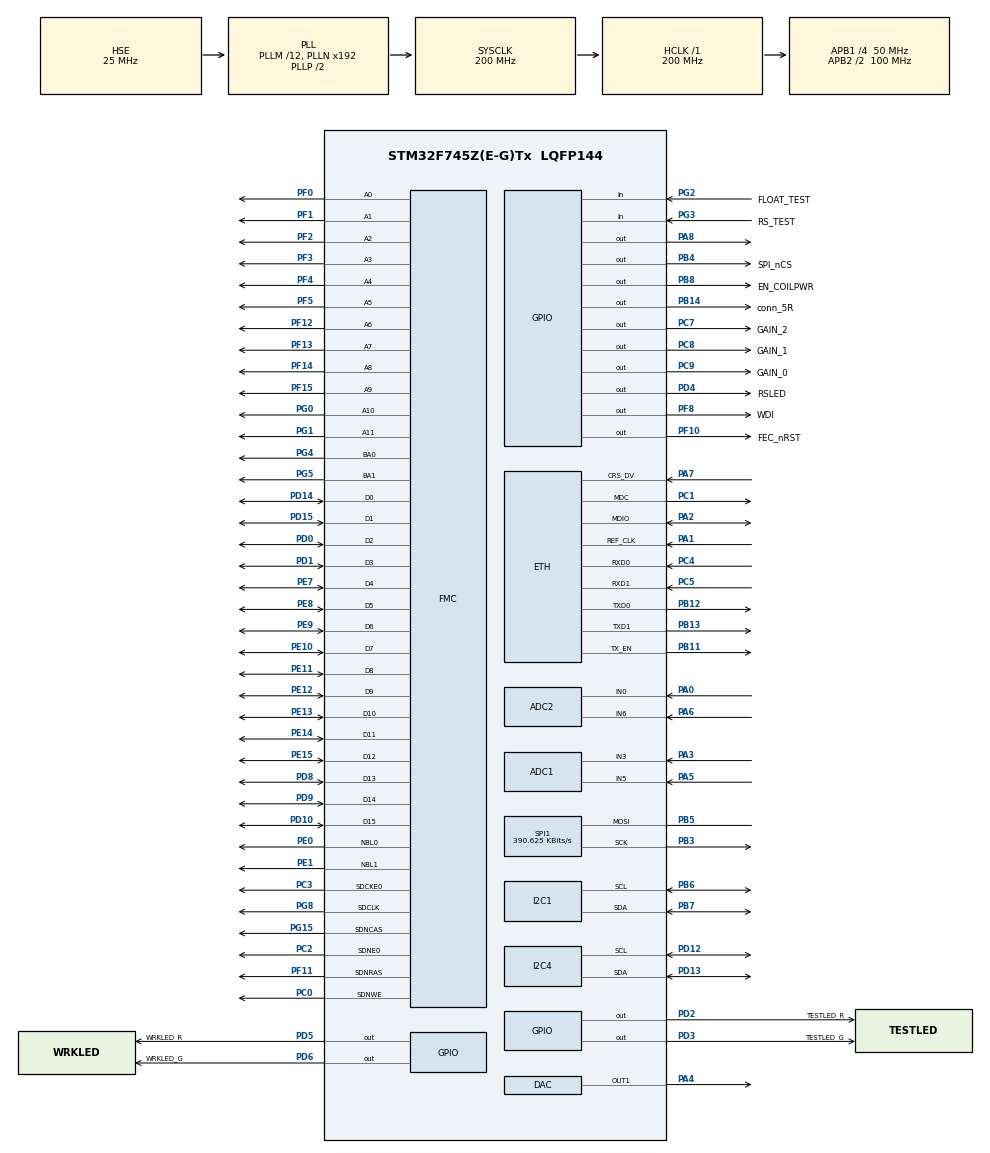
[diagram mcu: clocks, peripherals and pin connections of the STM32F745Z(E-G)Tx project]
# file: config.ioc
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ADC1.Channel-0\#ChannelRegularConversion=ADC_CHANNEL_3
ADC1.Channel-1\#ChannelRegularConversion=ADC_CHANNEL_3
ADC1.Channel-2\#ChannelRegularConversion=ADC_CHANNEL_3
ADC1.Channel-3\#ChannelRegularConversion=ADC_CHANNEL_3
ADC1.ClockPrescaler=ADC_CLOCK_SYNC_PCLK_DIV8
ADC1.ContinuousConvMode=ENABLE
ADC1.DMAContinuousRequests=ENABLE
ADC1.Mode=ADC_DUALMODE_REGSIMULT
ADC1.NbrOfConversion=4
ADC1.NbrOfConversionFlag=1
ADC1.Rank-0\#ChannelRegularConversion=1
ADC1.Rank-1\#ChannelRegularConversion=2
ADC1.Rank-2\#ChannelRegularConversion=3
ADC1.Rank-3\#ChannelRegularConversion=4
ADC1.SamplingTime-0\#ChannelRegularConversion=ADC_SAMPLETIME_3CYCLES
ADC1.SamplingTime-1\#ChannelRegularConversion=ADC_SAMPLETIME_3CYCLES
ADC1.SamplingTime-2\#ChannelRegularConversion=ADC_SAMPLETIME_3CYCLES
ADC1.SamplingTime-3\#ChannelRegularConversion=ADC_SAMPLETIME_3CYCLES
ADC1.master=1
ADC2.Channel-0\#ChannelRegularConversion=ADC_CHANNEL_0
ADC2.Channel-1\#ChannelRegularConversion=ADC_CHANNEL_0
ADC2.Channel-2\#ChannelRegularConversion=ADC_CHANNEL_0
ADC2.Channel-3\#ChannelRegularConversion=ADC_CHANNEL_0
ADC2.ClockPrescaler=ADC_CLOCK_SYNC_PCLK_DIV8
ADC2.ContinuousConvMode=ENABLE
ADC2.DMAAccessMode=ADC_DMAACCESSMODE_2
ADC2.Mode=ADC_DUALMODE_REGSIMULT
ADC2.NbrOfConversion=4
ADC2.NbrOfConversionFlag=1
ADC2.Rank-0\#ChannelRegularConversion=1
ADC2.Rank-1\#ChannelRegularConversion=2
ADC2.Rank-2\#ChannelRegularConversion=3
ADC2.Rank-3\#ChannelRegularConversion=4
ADC2.SamplingTime-0\#ChannelRegularConversion=ADC_SAMPLETIME_3CYCLES
ADC2.SamplingTime-1\#ChannelRegularConversion=ADC_SAMPLETIME_3CYCLES
ADC2.SamplingTime-2\#ChannelRegularConversion=ADC_SAMPLETIME_3CYCLES
ADC2.SamplingTime-3\#ChannelRegularConversion=ADC_SAMPLETIME_3CYCLES
CORTEX_M7.CPU_DCache=Enabled
CORTEX_M7.CPU_ICache=Enabled
CORTEX_M7.PREFETCH_ENABLE=1
DAC.DAC_Trigger=DAC_TRIGGER_SOFTWARE
Dma.ADC1.0.Direction=DMA_PERIPH_TO_MEMORY
Dma.ADC1.0.FIFOMode=DMA_FIFOMODE_DISABLE
Dma.ADC1.0.Instance=DMA2_Stream0
Dma.ADC1.0.MemDataAlignment=DMA_MDATAALIGN_WORD
Dma.ADC1.0.MemInc=DMA_MINC_ENABLE
Dma.ADC1.0.Mode=DMA_CIRCULAR
Dma.ADC1.0.PeriphDataAlignment=DMA_PDATAALIGN_WORD
Dma.ADC1.0.PeriphInc=DMA_PINC_DISABLE
Dma.ADC1.0.Priority=DMA_PRIORITY_HIGH
Dma.Request0=ADC1
ETH.MediaInterface=ETH_MEDIA_INTERFACE_RMII
ETH.PhyAddress=0
FMC.CASLatency1=FMC_SDRAM_CAS_LATENCY_2
FMC.ReadBurst1=FMC_SDRAM_RBURST_ENABLE
FMC.WriteProtection1=FMC_SDRAM_WRITE_PROTECTION_DISABLE
FREERTOS.Mutexes01=myMutex01,Dynamic,NULL
FREERTOS.Tasks01=defaultTask,0,128,StartDefaultTask,Default,NULL,Dynamic,NULL,NULL
FREERTOS.configENABLE_FPU=1
I2C1.Analog_Filter=I2C_ANALOGFILTER_DISABLE
I2C1.Timing=0x00C0EFFF
I2C4.Analog_Filter=I2C_ANALOGFILTER_DISABLE
I2C4.Timing=0x00C0EFFF
LWIP.GATEWAY_ADDRESS=192.168.000.001
LWIP.IP_ADDRESS=192.168.000.010
LWIP.LWIP_DHCP=0
LWIP.LWIP_HTTPD=0
LWIP.NETMASK_ADDRESS=255.255.255.000
LWIP.Version=v2.1.2_Cube
Mcu.Family=STM32F7
Mcu.Name=STM32F745Z(E-G)Tx
Mcu.Package=LQFP144
NVIC.DMA2_Stream0_IRQn=true\:0\:0\:false\:false\:true\:true\:false\:true
NVIC.ETH_IRQn=true\:0\:0\:false\:false\:true\:false\:true\:true
NVIC.PriorityGroup=NVIC_PRIORITYGROUP_4
NVIC.TIM1_UP_TIM10_IRQn=true\:0\:0\:false\:false\:true\:false\:true\:true
PA0/WKUP.Signal=ADCx_IN0
PA1.Mode=RMII
PA1.Signal=ETH_REF_CLK
PA13.Mode=Serial_Wire
PA13.Signal=SYS_JTMS-SWDIO
PA14.Mode=Serial_Wire
PA14.Signal=SYS_JTCK-SWCLK
PA2.Mode=RMII
PA2.Signal=ETH_MDIO
PA3.Signal=ADCx_IN3
PA4.Signal=COMP_DAC1_group
PA5.Signal=ADCx_IN5
PA6.Signal=ADCx_IN6
PA7.Mode=RMII
PA7.Signal=ETH_CRS_DV
PA8.Signal=GPIO_Output
PB11.Mode=RMII
PB11.Signal=ETH_TX_EN
PB12.Mode=RMII
PB12.Signal=ETH_TXD0
PB13.Mode=RMII
PB13.Signal=ETH_TXD1
PB14.GPIO_Label=conn_5R
PB14.Signal=GPIO_Output
PB3.Mode=Simplex_Bidirectional_Master
PB3.Signal=SPI1_SCK
PB4.GPIO_Label=SPI_nCS
PB4.Signal=GPIO_Output
PB5.Mode=Simplex_Bidirectional_Master
PB5.Signal=SPI1_MOSI
PB6.Mode=I2C
PB6.Signal=I2C1_SCL
PB7.Mode=I2C
PB7.Signal=I2C1_SDA
PB8.GPIO_Label=EN_COILPWR
PB8.Signal=GPIO_Output
PC0.Signal=FMC_SDNWE
PC1.Mode=RMII
PC1.Signal=ETH_MDC
PC2.Mode=SdramChipSelect1_1
PC2.Signal=FMC_SDNE0
PC3.Mode=SdramChipSelect1_1
PC3.Signal=FMC_SDCKE0
PC4.Mode=RMII
PC4.Signal=ETH_RXD0
PC5.Mode=RMII
PC5.Signal=ETH_RXD1
PC7.GPIO_Label=GAIN_2
PC7.Signal=GPIO_Output
PC8.GPIO_Label=GAIN_1
PC8.Signal=GPIO_Output
PC9.GPIO_Label=GAIN_0
PC9.Signal=GPIO_Output
PD0.Signal=FMC_D2_DA2
PD1.Signal=FMC_D3_DA3
PD10.Signal=FMC_D15_DA15
PD12.Mode=I2C
PD12.Signal=I2C4_SCL
PD13.Mode=I2C
PD13.Signal=I2C4_SDA
PD14.Signal=FMC_D0_DA0
PD15.Signal=FMC_D1_DA1
PD2.GPIO_Label=TESTLED_R
PD2.Signal=GPIO_Output
PD3.GPIO_Label=TESTLED_G
PD3.Signal=GPIO_Output
PD4.GPIO_Label=RSLED
PD4.Signal=GPIO_Output
PD5.GPIO_Label=WRKLED_R
PD5.Signal=GPIO_Output
PD6.GPIO_Label=WRKLED_G
PD6.Signal=GPIO_Output
PD8.Signal=FMC_D13_DA13
PD9.Signal=FMC_D14_DA14
PE0.Signal=FMC_NBL0
PE1.Signal=FMC_NBL1
PE10.Signal=FMC_D7_DA7
PE11.Signal=FMC_D8_DA8
PE12.Signal=FMC_D9_DA9
PE13.Signal=FMC_D10_DA10
PE14.Signal=FMC_D11_DA11
PE15.Signal=FMC_D12_DA12
PE7.Signal=FMC_D4_DA4
PE8.Signal=FMC_D5_DA5
PE9.Signal=FMC_D6_DA6
PF0.Signal=FMC_A0
PF1.Signal=FMC_A1
PF10.GPIO_Label=FEC_nRST
PF10.Signal=GPIO_Output
PF11.Signal=FMC_SDNRAS
PF12.Signal=FMC_A6
PF13.Signal=FMC_A7
PF14.Signal=FMC_A8
PF15.Signal=FMC_A9
PF2.Signal=FMC_A2
PF3.Signal=FMC_A3
PF4.Signal=FMC_A4
PF5.Signal=FMC_A5
PF8.GPIO_Label=WDI
PF8.Signal=GPIO_Output
PG0.Signal=FMC_A10
PG1.Signal=FMC_A11
PG15.Signal=FMC_SDNCAS
PG2.GPIO_Label=FLOAT_TEST
PG2.Signal=GPIO_Input
PG3.GPIO_Label=RS_TEST
PG3.Signal=GPIO_Input
PG4.Signal=FMC_A14_BA0
PG5.Signal=FMC_A15_BA1
PG8.Signal=FMC_SDCLK
PH0/OSC_IN.Mode=HSE-External-Oscillator
PH0/OSC_IN.Signal=RCC_OSC_IN
PH1/OSC_OUT.Mode=HSE-External-Oscillator
PH1/OSC_OUT.Signal=RCC_OSC_OUT
ProjectManager.HeapSize=0x200
ProjectManager.StackSize=0x400
ProjectManager.TargetToolchain=EWARM V8.32
RCC.AHBFreq_Value=200000000
RCC.APB1CLKDivider=RCC_HCLK_DIV4
RCC.APB1Freq_Value=50000000
RCC.APB1TimFreq_Value=100000000
RCC.APB2CLKDivider=RCC_HCLK_DIV2
RCC.APB2Freq_Value=100000000
RCC.APB2TimFreq_Value=200000000
RCC.CortexFreq_Value=200000000
RCC.HCLKFreq_Value=200000000
RCC.HSE_VALUE=25000000
RCC.HSI_VALUE=16000000
RCC.LSE_VALUE=32768
RCC.PLLM=12
RCC.PLLSourceVirtual=RCC_PLLSOURCE_HSE
RCC.SYSCLKFreq_VALUE=200000000
RCC.SYSCLKSource=RCC_SYSCLKSOURCE_PLLCLK
RCC.USBFreq_Value=200000000
RCC.VCOOutputFreq_Value=400000000
SH.ADCx_IN0.0=ADC2_IN0,IN0
SH.ADCx_IN3.0=ADC1_IN3,IN3
SH.ADCx_IN5.0=ADC1_IN5,IN5
SH.ADCx_IN6.0=ADC2_IN6,IN6
SH.COMP_DAC1_group.0=DAC_OUT1,DAC_OUT1
SH.FMC_A0.0=FMC_A0,12b-sda1
SH.FMC_A1.0=FMC_A1,12b-sda1
SH.FMC_A10.0=FMC_A10,12b-sda1
SH.FMC_A11.0=FMC_A11,12b-sda1
SH.FMC_A14_BA0.0=FMC_BA0,FourSdramBanks1
SH.FMC_A15_BA1.0=FMC_BA1,FourSdramBanks1
SH.FMC_A2.0=FMC_A2,12b-sda1
SH.FMC_A3.0=FMC_A3,12b-sda1
SH.FMC_A4.0=FMC_A4,12b-sda1
SH.FMC_A5.0=FMC_A5,12b-sda1
SH.FMC_A6.0=FMC_A6,12b-sda1
SH.FMC_A7.0=FMC_A7,12b-sda1
SH.FMC_A8.0=FMC_A8,12b-sda1
SH.FMC_A9.0=FMC_A9,12b-sda1
SH.FMC_D0_DA0.0=FMC_D0,sd-16b-d1
SH.FMC_D10_DA10.0=FMC_D10,sd-16b-d1
SH.FMC_D11_DA11.0=FMC_D11,sd-16b-d1
SH.FMC_D12_DA12.0=FMC_D12,sd-16b-d1
SH.FMC_D13_DA13.0=FMC_D13,sd-16b-d1
SH.FMC_D14_DA14.0=FMC_D14,sd-16b-d1
SH.FMC_D15_DA15.0=FMC_D15,sd-16b-d1
SH.FMC_D1_DA1.0=FMC_D1,sd-16b-d1
SH.FMC_D2_DA2.0=FMC_D2,sd-16b-d1
SH.FMC_D3_DA3.0=FMC_D3,sd-16b-d1
SH.FMC_D4_DA4.0=FMC_D4,sd-16b-d1
SH.FMC_D5_DA5.0=FMC_D5,sd-16b-d1
SH.FMC_D6_DA6.0=FMC_D6,sd-16b-d1
SH.FMC_D7_DA7.0=FMC_D7,sd-16b-d1
SH.FMC_D8_DA8.0=FMC_D8,sd-16b-d1
SH.FMC_D9_DA9.0=FMC_D9,sd-16b-d1
SH.FMC_NBL0.0=FMC_NBL0,Sd2ByteEnable1
SH.FMC_NBL1.0=FMC_NBL1,Sd2ByteEnable1
SH.FMC_SDCLK.0=FMC_SDCLK,12b-sda1
SH.FMC_SDNCAS.0=FMC_SDNCAS,12b-sda1
SH.FMC_SDNRAS.0=FMC_SDNRAS,12b-sda1
SH.FMC_SDNWE.0=FMC_SDNWE,12b-sda1
SPI1.BaudRatePrescaler=SPI_BAUDRATEPRESCALER_256
SPI1.CLKPhase=SPI_PHASE_2EDGE
SPI1.CalculateBaudRate=390.625 KBits/s
SPI1.DataSize=SPI_DATASIZE_8BIT
SPI1.Direction=SPI_DIRECTION_1LINE
SPI1.Mode=SPI_MODE_MASTER
SPI1.VirtualType=VM_MASTER
TIM1.AutoReloadPreload=TIM_AUTORELOAD_PRELOAD_ENABLE
TIM1.Channel-Output\ Compare1\ No\ Output=TIM_CHANNEL_1
TIM1.Period=256
TIM1.Prescaler=1000
VP_FREERTOS_VS_CMSIS_V1.Mode=CMSIS_V1
VP_LWIP_VS_Enabled.Mode=Enabled
VP_TIM1_VS_ClockSourceINT.Mode=Internal
VP_TIM1_VS_no_output1.Mode=Output Compare1 No Output
board=custom

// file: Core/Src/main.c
/* USER CODE BEGIN Header */
/**
 ******************************************************************************
 * @file           : main.c
 * @brief          : Main program body
 ******************************************************************************
 * @attention
 *
 * <h2><center>&copy; Copyright (c) 2021 STMicroelectronics.
 * All rights reserved.</center></h2>
 *
 * This software component is licensed by ST under Ultimate Liberty license
 * SLA0044, the "License"; You may not use this file except in compliance with
 * the License. You may obtain a copy of the License at:
 *                             www.st.com/SLA0044
 *
 ******************************************************************************
 */
/* USER CODE END Header */
#include "main.h"
#include "cmsis_os.h"
#include "lwip.h"
#include "eeprom.h"
#include "httpd.h"
#include "analog.h"
#include "process.h"
#include "http_server.h"

ADC_HandleTypeDef hadc1;
ADC_HandleTypeDef hadc2;
DMA_HandleTypeDef hdma_adc1;

DAC_HandleTypeDef hdac;

I2C_HandleTypeDef hi2c1;
I2C_HandleTypeDef hi2c4;

TIM_HandleTypeDef htim1;
SPI_HandleTypeDef hspi1;

SDRAM_HandleTypeDef hsdram1;

osThreadId defaultTaskHandle;
osThreadId AnalogMeashureHandle;
osThreadId AlgorithmHandle;
osThreadId HTTPServerHandle;

void SystemClock_Config(void);
static void MX_GPIO_Init(void);
static void MX_DMA_Init(void);
static void MX_ADC1_Init(void);
static void MX_ADC2_Init(void);
static void MX_DAC_Init(void);
static void MX_I2C1_Init(void);
static void MX_TIM1_Init(void);
static void MX_FMC_Init(void);
static void SDRAM_Initialization_Sequence(SDRAM_HandleTypeDef *hsdram, FMC_SDRAM_CommandTypeDef *Command);
static void MX_I2C4_Init(void);
static void MX_SPI1_Init(void);
void StartDefaultTask(void const *argument);

int main(void)
{
  FMC_SDRAM_CommandTypeDef command;

#define BUFFER_SIZE ((uint32_t)0x1000)
#define WRITE_READ_ADDR ((uint32_t)0x0800)
#define SDRAM_BANK_ADDR ((uint32_t)0xC0000000)
  // uint32_t aTxBuffer[BUFFER_SIZE];
  // uint32_t aRxBuffer[BUFFER_SIZE];
  uint32_t uwIndex = 0;
  __IO uint32_t uwWriteReadStatus = 0;

  /* Enable I-Cache---------------------------------------------------------*/
  SCB_EnableICache();

  /* Enable D-Cache---------------------------------------------------------*/
  SCB_EnableDCache();

  /* MCU Configuration--------------------------------------------------------*/

  /* Reset of all peripherals, Initializes the Flash interface and the Systick. */
  HAL_Init();

  /* Configure the system clock */
  SystemClock_Config();

  /* Initialize all configured peripherals */
  MX_GPIO_Init();
  MX_DMA_Init();
  MX_ADC1_Init();
  MX_ADC2_Init();
  MX_DAC_Init();
  MX_I2C1_Init();
  MX_TIM1_Init();
  MX_FMC_Init();
  SDRAM_Initialization_Sequence(&hsdram1, &command);
  MX_I2C4_Init();
  MX_SPI1_Init();

  /* Write data to the SDRAM memory */

  //  for (uwIndex = 0; uwIndex < BUFFER_SIZE; uwIndex++)
  //  {
  //    *(__IO uint16_t*) (SDRAM_BANK_ADDR + WRITE_READ_ADDR + 2*uwIndex) = uwIndex;
  //  }
  //
  //  /* Read back data from the SDRAM memory */
  //  for (uwIndex = 0; uwIndex < BUFFER_SIZE; uwIndex++)
  //  {
  //    aRxBuffer[uwIndex] = *(__IO uint16_t*) (SDRAM_BANK_ADDR + WRITE_READ_ADDR + 2*uwIndex);
  //  }
  //
  //  /*##-3- Checking data integrity ############################################*/
  //
  //  for (uwIndex = 0; (uwIndex < BUFFER_SIZE) && (uwWriteReadStatus == 0); uwIndex++)
  //  {
  //    if (aRxBuffer[uwIndex] != aTxBuffer[uwIndex])
  //    {
  //      uwWriteReadStatus++;
  //    }
  //  }
  //
  //
  HAL_DAC_Start(&hdac, DAC_CHANNEL_1);
  HAL_DAC_SetValue(&hdac, DAC_CHANNEL_1, DAC_ALIGN_12B_R, 0);
  /* USER CODE BEGIN 2 */
  /*reset eth phy*/
  int idx = 1024;
  HAL_GPIO_WritePin(FEC_nRST_GPIO_Port, FEC_nRST_Pin, GPIO_PIN_RESET);
  while (idx--)
    ;
  idx = 1024;
  HAL_GPIO_WritePin(FEC_nRST_GPIO_Port, FEC_nRST_Pin, GPIO_PIN_SET);
  while (idx--)
    ;

  /* USER CODE END 2 */

  /* Create the thread(s) */
  /* definition and creation of defaultTask */
  osThreadDef(defaultTask, StartDefaultTask, osPriorityNormal, 0, 1024);
  defaultTaskHandle = osThreadCreate(osThread(defaultTask), NULL);

  osThreadDef(AlgorithmTask, Algorithm, osPriorityNormal, 0, 1024);
  AlgorithmHandle = osThreadCreate(osThread(AlgorithmTask), NULL);

  osThreadDef(AnalogMeashureTask, AnalogMeashure, osPriorityNormal, 0, 1024);
  AnalogMeashureHandle = osThreadCreate(osThread(AnalogMeashureTask), NULL);

  /* USER CODE BEGIN RTOS_THREADS */
  /* add threads, ... */
  CreateEEPROMSemaphore();
  /* USER CODE END RTOS_THREADS */

  /* Start scheduler */
  osKernelStart();

  /* We should never get here as control is now taken by the scheduler */
  /* Infinite loop */
  while (1)
  {
    /*ToDo:
      ������ ��������� (��� � �����������)
      ������� ����� �+Js
      ��������� ���� �� ������ �� �������
      process.c - ��������� ��� ������� ����������� ������

  */
  }
}

void SystemClock_Config(void)
{
  RCC_OscInitTypeDef RCC_OscInitStruct = {0};
  RCC_ClkInitTypeDef RCC_ClkInitStruct = {0};
  RCC_PeriphCLKInitTypeDef PeriphClkInitStruct = {0};

  /** Configure the main internal regulator output voltage
   */
  __HAL_RCC_PWR_CLK_ENABLE();
  __HAL_PWR_VOLTAGESCALING_CONFIG(PWR_REGULATOR_VOLTAGE_SCALE1);
  /** Initializes the RCC Oscillators according to the specified parameters
   * in the RCC_OscInitTypeDef structure.
   */
  RCC_OscInitStruct.OscillatorType = RCC_OSCILLATORTYPE_HSE;
  RCC_OscInitStruct.HSEState = RCC_HSE_ON;
  RCC_OscInitStruct.PLL.PLLState = RCC_PLL_ON;
  RCC_OscInitStruct.PLL.PLLSource = RCC_PLLSOURCE_HSE;
  RCC_OscInitStruct.PLL.PLLM = 12;  // 12
  RCC_OscInitStruct.PLL.PLLN = 192; // 192
  RCC_OscInitStruct.PLL.PLLP = RCC_PLLP_DIV2;
  RCC_OscInitStruct.PLL.PLLQ = 2;
  if (HAL_RCC_OscConfig(&RCC_OscInitStruct) != HAL_OK)
  {
    Error_Handler();
  }
  /** Activate the Over-Drive mode
   */
  if (HAL_PWREx_EnableOverDrive() != HAL_OK)
  {
    Error_Handler();
  }
  /** Initializes the CPU, AHB and APB buses clocks
   */
  RCC_ClkInitStruct.ClockType = RCC_CLOCKTYPE_HCLK | RCC_CLOCKTYPE_SYSCLK | RCC_CLOCKTYPE_PCLK1 | RCC_CLOCKTYPE_PCLK2;
  RCC_ClkInitStruct.SYSCLKSource = RCC_SYSCLKSOURCE_PLLCLK;
  RCC_ClkInitStruct.AHBCLKDivider = RCC_SYSCLK_DIV1;
  RCC_ClkInitStruct.APB1CLKDivider = RCC_HCLK_DIV4;
  RCC_ClkInitStruct.APB2CLKDivider = RCC_HCLK_DIV2;

  if (HAL_RCC_ClockConfig(&RCC_ClkInitStruct, FLASH_LATENCY_6) != HAL_OK)
  {
    Error_Handler();
  }
  PeriphClkInitStruct.PeriphClockSelection = RCC_PERIPHCLK_I2C1 | RCC_PERIPHCLK_I2C4;
  PeriphClkInitStruct.I2c1ClockSelection = RCC_I2C1CLKSOURCE_PCLK1;
  PeriphClkInitStruct.I2c4ClockSelection = RCC_I2C4CLKSOURCE_PCLK1;
  if (HAL_RCCEx_PeriphCLKConfig(&PeriphClkInitStruct) != HAL_OK)
  {
    Error_Handler();
  }
}

/*Fadc=833 kHz*/
static void MX_ADC1_Init(void)
{

  ADC_MultiModeTypeDef multimode = {0};
  ADC_ChannelConfTypeDef sConfig = {0};

  /** Common config
   */

  hadc1.Instance = ADC1;
  hadc1.Init.ClockPrescaler = ADC_CLOCK_SYNC_PCLK_DIV6;
  hadc1.Init.Resolution = ADC_RESOLUTION_12B;
  hadc1.Init.ScanConvMode = ADC_SCAN_ENABLE;
  hadc1.Init.ContinuousConvMode = ENABLE;
  hadc1.Init.DiscontinuousConvMode = DISABLE;
  hadc1.Init.ExternalTrigConvEdge = ADC_EXTERNALTRIGCONVEDGE_NONE;
  hadc1.Init.ExternalTrigConv = ADC_SOFTWARE_START;
  hadc1.Init.DataAlign = ADC_DATAALIGN_RIGHT;
  hadc1.Init.NbrOfConversion = 4;
  hadc1.Init.DMAContinuousRequests = ENABLE;
  hadc1.Init.EOCSelection = ADC_EOC_SINGLE_CONV;
  if (HAL_ADC_Init(&hadc1) != HAL_OK)
  {
    Error_Handler();
  }
  /** Configure the ADC multi-mode
   */
  multimode.Mode = ADC_DUALMODE_REGSIMULT;
  multimode.DMAAccessMode = ADC_DMAACCESSMODE_2;
  multimode.TwoSamplingDelay = ADC_TWOSAMPLINGDELAY_5CYCLES;
  if (HAL_ADCEx_MultiModeConfigChannel(&hadc1, &multimode) != HAL_OK)
  {
    Error_Handler();
  }
  /** Configure Regular Channel
   */
  sConfig.Channel = ADC_CHANNEL_3;
  sConfig.Rank = ADC_REGULAR_RANK_1;
  sConfig.SamplingTime = ADC_SAMPLETIME_3CYCLES;
  if (HAL_ADC_ConfigChannel(&hadc1, &sConfig) != HAL_OK)
  {
    Error_Handler();
  }
  /** Configure Regular Channel
   */
  sConfig.Channel = ADC_CHANNEL_5;
  sConfig.Rank = ADC_REGULAR_RANK_2;
  if (HAL_ADC_ConfigChannel(&hadc1, &sConfig) != HAL_OK)
  {
    Error_Handler();
  }
  /** Configure Regular Channel
   */
  sConfig.Channel = ADC_CHANNEL_3;
  sConfig.Rank = ADC_REGULAR_RANK_3;
  if (HAL_ADC_ConfigChannel(&hadc1, &sConfig) != HAL_OK)
  {
    Error_Handler();
  }
  sConfig.Channel = ADC_CHANNEL_5;
  sConfig.Rank = ADC_REGULAR_RANK_4;
  if (HAL_ADC_ConfigChannel(&hadc1, &sConfig) != HAL_OK)
  {
    Error_Handler();
  }

}

/*3 samples are token every 5 mks*/
static void MX_ADC2_Init(void)
{

  ADC_ChannelConfTypeDef sConfig = {0};

  /** Common config
   */
  hadc2.Instance = ADC2;
  hadc2.Init.ClockPrescaler = ADC_CLOCK_SYNC_PCLK_DIV8;
  hadc2.Init.Resolution = ADC_RESOLUTION_12B;
  hadc2.Init.ScanConvMode = ADC_SCAN_ENABLE;
  hadc2.Init.ContinuousConvMode = ENABLE;
  hadc2.Init.DiscontinuousConvMode = DISABLE;
  hadc2.Init.ExternalTrigConvEdge = ADC_EXTERNALTRIGCONVEDGE_NONE;
  hadc2.Init.ExternalTrigConv = ADC_SOFTWARE_START;
  hadc2.Init.DataAlign = ADC_DATAALIGN_RIGHT;
  hadc2.Init.NbrOfConversion = 4;
  hadc2.Init.DMAContinuousRequests = DISABLE;
  hadc2.Init.EOCSelection = ADC_EOC_SINGLE_CONV;
  if (HAL_ADC_Init(&hadc2) != HAL_OK)
  {
    Error_Handler();
  }
  /** Configure Regular Channel
   */
  sConfig.Channel = ADC_CHANNEL_0;
  sConfig.Rank = ADC_REGULAR_RANK_1;
  sConfig.SamplingTime = ADC_SAMPLETIME_3CYCLES;
  if (HAL_ADC_ConfigChannel(&hadc2, &sConfig) != HAL_OK)
  {
    Error_Handler();
  }
  /** Configure Regular Channel
   */
  sConfig.Channel = ADC_CHANNEL_6;
  sConfig.Rank = ADC_REGULAR_RANK_2;
  if (HAL_ADC_ConfigChannel(&hadc2, &sConfig) != HAL_OK)
  {
    Error_Handler();
  }
  /** Configure Regular Channel
   */
  sConfig.Channel = ADC_CHANNEL_0;
  sConfig.Rank = ADC_REGULAR_RANK_3;
  if (HAL_ADC_ConfigChannel(&hadc2, &sConfig) != HAL_OK)
  {
    Error_Handler();
  }
  sConfig.Channel = ADC_CHANNEL_6;
  sConfig.Rank = ADC_REGULAR_RANK_4;
  if (HAL_ADC_ConfigChannel(&hadc2, &sConfig) != HAL_OK)
  {
    Error_Handler();
  }

}

static void MX_DAC_Init(void)
{

  DAC_ChannelConfTypeDef sConfig = {0};

  /** DAC Initialization
   */
  hdac.Instance = DAC;
  if (HAL_DAC_Init(&hdac) != HAL_OK)
  {
    Error_Handler();
  }
  /** DAC channel OUT1 config
   */
  sConfig.DAC_Trigger = DAC_TRIGGER_NONE;
  sConfig.DAC_OutputBuffer = DAC_OUTPUTBUFFER_ENABLE;
  if (HAL_DAC_ConfigChannel(&hdac, &sConfig, DAC_CHANNEL_1) != HAL_OK)
  {
    Error_Handler();
  }
}

static void MX_I2C1_Init(void)
{

  hi2c1.Instance = I2C1;
  hi2c1.Init.Timing = 0x00C0EFFF;
  hi2c1.Init.OwnAddress1 = 0;
  hi2c1.Init.AddressingMode = I2C_ADDRESSINGMODE_7BIT;
  hi2c1.Init.DualAddressMode = I2C_DUALADDRESS_DISABLE;
  hi2c1.Init.OwnAddress2 = 0;
  hi2c1.Init.OwnAddress2Masks = I2C_OA2_NOMASK;
  hi2c1.Init.GeneralCallMode = I2C_GENERALCALL_DISABLE;
  hi2c1.Init.NoStretchMode = I2C_NOSTRETCH_DISABLE;
  if (HAL_I2C_Init(&hi2c1) != HAL_OK)
  {
    Error_Handler();
  }
  /** Configure Analogue filter
   */
  if (HAL_I2CEx_ConfigAnalogFilter(&hi2c1, I2C_ANALOGFILTER_DISABLE) != HAL_OK)
  {
    Error_Handler();
  }
  /** Configure Digital filter
   */
  if (HAL_I2CEx_ConfigDigitalFilter(&hi2c1, 0) != HAL_OK)
  {
    Error_Handler();
  }
}

static void MX_I2C4_Init(void)
{

  hi2c4.Instance = I2C4;
  hi2c4.Init.Timing = 0x00C0EFFF;
  hi2c4.Init.OwnAddress1 = 0;
  hi2c4.Init.AddressingMode = I2C_ADDRESSINGMODE_7BIT;
  hi2c4.Init.DualAddressMode = I2C_DUALADDRESS_DISABLE;
  hi2c4.Init.OwnAddress2 = 0;
  hi2c4.Init.OwnAddress2Masks = I2C_OA2_NOMASK;
  hi2c4.Init.GeneralCallMode = I2C_GENERALCALL_DISABLE;
  hi2c4.Init.NoStretchMode = I2C_NOSTRETCH_DISABLE;
  if (HAL_I2C_Init(&hi2c4) != HAL_OK)
  {
    Error_Handler();
  }
  /** Configure Analogue filter
   */
  if (HAL_I2CEx_ConfigAnalogFilter(&hi2c4, I2C_ANALOGFILTER_DISABLE) != HAL_OK)
  {
    Error_Handler();
  }
  /** Configure Digital filter
   */
  if (HAL_I2CEx_ConfigDigitalFilter(&hi2c4, 0) != HAL_OK)
  {
    Error_Handler();
  }
}

static void MX_TIM1_Init(void)
{

  TIM_ClockConfigTypeDef sClockSourceConfig = {0};
  TIM_MasterConfigTypeDef sMasterConfig = {0};
  TIM_OC_InitTypeDef sConfigOC = {0};
  TIM_BreakDeadTimeConfigTypeDef sBreakDeadTimeConfig = {0};

  htim1.Instance = TIM1;
  htim1.Init.Prescaler = 2500;
  htim1.Init.CounterMode = TIM_COUNTERMODE_UP;
  htim1.Init.Period = 256;
  htim1.Init.ClockDivision = TIM_CLOCKDIVISION_DIV1;
  htim1.Init.RepetitionCounter = 0;
  htim1.Init.AutoReloadPreload = TIM_AUTORELOAD_PRELOAD_ENABLE;
  if (HAL_TIM_Base_Init(&htim1) != HAL_OK)
  {
    Error_Handler();
  }
  sClockSourceConfig.ClockSource = TIM_CLOCKSOURCE_INTERNAL;
  if (HAL_TIM_ConfigClockSource(&htim1, &sClockSourceConfig) != HAL_OK)
  {
    Error_Handler();
  }
  if (HAL_TIM_OC_Init(&htim1) != HAL_OK)
  {
    Error_Handler();
  }
  sMasterConfig.MasterOutputTrigger = TIM_TRGO_RESET;
  sMasterConfig.MasterOutputTrigger2 = TIM_TRGO2_RESET;
  sMasterConfig.MasterSlaveMode = TIM_MASTERSLAVEMODE_DISABLE;
  if (HAL_TIMEx_MasterConfigSynchronization(&htim1, &sMasterConfig) != HAL_OK)
  {
    Error_Handler();
  }
  sConfigOC.OCMode = TIM_OCMODE_TIMING;
  sConfigOC.Pulse = 0;
  sConfigOC.OCPolarity = TIM_OCPOLARITY_HIGH;
  sConfigOC.OCNPolarity = TIM_OCNPOLARITY_HIGH;
  sConfigOC.OCFastMode = TIM_OCFAST_DISABLE;
  sConfigOC.OCIdleState = TIM_OCIDLESTATE_RESET;
  sConfigOC.OCNIdleState = TIM_OCNIDLESTATE_RESET;
  if (HAL_TIM_OC_ConfigChannel(&htim1, &sConfigOC, TIM_CHANNEL_1) != HAL_OK)
  {
    Error_Handler();
  }
  sBreakDeadTimeConfig.OffStateRunMode = TIM_OSSR_DISABLE;
  sBreakDeadTimeConfig.OffStateIDLEMode = TIM_OSSI_DISABLE;
  sBreakDeadTimeConfig.LockLevel = TIM_LOCKLEVEL_OFF;
  sBreakDeadTimeConfig.DeadTime = 0;
  sBreakDeadTimeConfig.BreakState = TIM_BREAK_DISABLE;
  sBreakDeadTimeConfig.BreakPolarity = TIM_BREAKPOLARITY_HIGH;
  sBreakDeadTimeConfig.BreakFilter = 0;
  sBreakDeadTimeConfig.Break2State = TIM_BREAK2_DISABLE;
  sBreakDeadTimeConfig.Break2Polarity = TIM_BREAK2POLARITY_HIGH;
  sBreakDeadTimeConfig.Break2Filter = 0;
  sBreakDeadTimeConfig.AutomaticOutput = TIM_AUTOMATICOUTPUT_DISABLE;
  if (HAL_TIMEx_ConfigBreakDeadTime(&htim1, &sBreakDeadTimeConfig) != HAL_OK)
  {
    Error_Handler();
  }
}

static void MX_DMA_Init(void)
{

  /* DMA controller clock enable */
  __HAL_RCC_DMA2_CLK_ENABLE();

  /* DMA interrupt init */
  /* DMA2_Stream0_IRQn interrupt configuration */
  HAL_NVIC_SetPriority(DMA2_Stream0_IRQn, 5, 0);
  HAL_NVIC_EnableIRQ(DMA2_Stream0_IRQn);
}

static void SDRAM_Initialization_Sequence(SDRAM_HandleTypeDef *hsdram, FMC_SDRAM_CommandTypeDef *Command)
{
  __IO uint32_t tmpmrd = 0;
  /* Step 1:  Configure a clock configuration enable command */
  Command->CommandMode = FMC_SDRAM_CMD_CLK_ENABLE;
  Command->CommandTarget = FMC_SDRAM_CMD_TARGET_BANK1;
  Command->AutoRefreshNumber = 1;
  Command->ModeRegisterDefinition = 0;

  /* Send the command */
  HAL_SDRAM_SendCommand(hsdram, Command, 0x1000);

  /* Step 2: Insert 100 us minimum delay */
  /* Inserted delay is equal to 1 ms due to systick time base unit (ms) */
  HAL_Delay(1);

  /* Step 3: Configure a PALL (precharge all) command */
  Command->CommandMode = FMC_SDRAM_CMD_PALL;
  Command->CommandTarget = FMC_SDRAM_CMD_TARGET_BANK1;
  Command->AutoRefreshNumber = 1;
  Command->ModeRegisterDefinition = 0;

  /* Send the command */
  HAL_SDRAM_SendCommand(hsdram, Command, 0x1000);

  /* Step 4 : Configure a Auto-Refresh command */
  Command->CommandMode = FMC_SDRAM_CMD_AUTOREFRESH_MODE;
  Command->CommandTarget = FMC_SDRAM_CMD_TARGET_BANK1;
  Command->AutoRefreshNumber = 8;
  Command->ModeRegisterDefinition = 0;

  /* Send the command */
  HAL_SDRAM_SendCommand(hsdram, Command, 0x1000);

  /* Step 5: Program the external memory mode register */
  tmpmrd = (uint32_t)SDRAM_MODEREG_BURST_LENGTH_1 |
           SDRAM_MODEREG_BURST_TYPE_SEQUENTIAL |
           SDRAM_MODEREG_CAS_LATENCY_3 |
           SDRAM_MODEREG_OPERATING_MODE_STANDARD |
           SDRAM_MODEREG_WRITEBURST_MODE_SINGLE;

  Command->CommandMode = FMC_SDRAM_CMD_LOAD_MODE;
  Command->CommandTarget = FMC_SDRAM_CMD_TARGET_BANK1;
  Command->AutoRefreshNumber = 1;
  Command->ModeRegisterDefinition = tmpmrd;

  /* Send the command */
  HAL_SDRAM_SendCommand(hsdram, Command, 0x1000);

  /* Step 6: Set the refresh rate counter */
  /* (15.62 us x Freq) - 20 */
  /* Set the device refresh counter */
  hsdram->Instance->SDRTR |= ((uint32_t)((1292) << 1));
}

/* FMC initialization function */
static void MX_FMC_Init(void)
{

  FMC_SDRAM_TimingTypeDef SdramTiming = {0};

  /** Perform the SDRAM1 memory initialization sequence
   */
  hsdram1.Instance = FMC_SDRAM_DEVICE;
  /* hsdram1.Init */
  hsdram1.Init.SDBank = FMC_SDRAM_BANK1;
  hsdram1.Init.ColumnBitsNumber = FMC_SDRAM_COLUMN_BITS_NUM_8;
  hsdram1.Init.RowBitsNumber = FMC_SDRAM_ROW_BITS_NUM_12;
  hsdram1.Init.MemoryDataWidth = FMC_SDRAM_MEM_BUS_WIDTH_16;
  hsdram1.Init.InternalBankNumber = FMC_SDRAM_INTERN_BANKS_NUM_4;
  hsdram1.Init.CASLatency = FMC_SDRAM_CAS_LATENCY_2;
  hsdram1.Init.WriteProtection = FMC_SDRAM_WRITE_PROTECTION_DISABLE;
  hsdram1.Init.SDClockPeriod = SDCLOCK_PERIOD;
  hsdram1.Init.ReadBurst = FMC_SDRAM_RBURST_ENABLE;
  hsdram1.Init.ReadPipeDelay = FMC_SDRAM_RPIPE_DELAY_0;
  /* SdramTiming */
  SdramTiming.LoadToActiveDelay = 2;
  SdramTiming.ExitSelfRefreshDelay = 6;
  SdramTiming.SelfRefreshTime = 4;
  SdramTiming.RowCycleDelay = 6;
  SdramTiming.WriteRecoveryTime = 2;
  SdramTiming.RPDelay = 2;
  SdramTiming.RCDDelay = 2;

  if (HAL_SDRAM_Init(&hsdram1, &SdramTiming) != HAL_OK)
  {
    Error_Handler();
  }

}

static void MX_SPI1_Init(void)
{

  /* SPI1 parameter configuration*/
  hspi1.Instance = SPI1;
  hspi1.Init.Mode = SPI_MODE_MASTER;
  hspi1.Init.Direction = SPI_DIRECTION_1LINE;
  hspi1.Init.DataSize = SPI_DATASIZE_8BIT;
  hspi1.Init.CLKPolarity = SPI_POLARITY_HIGH;
  hspi1.Init.CLKPhase = SPI_PHASE_1EDGE;
  hspi1.Init.NSS = SPI_NSS_SOFT;
  hspi1.Init.BaudRatePrescaler = SPI_BAUDRATEPRESCALER_256;
  hspi1.Init.FirstBit = SPI_FIRSTBIT_MSB;
  hspi1.Init.TIMode = SPI_TIMODE_DISABLE;
  hspi1.Init.CRCCalculation = SPI_CRCCALCULATION_DISABLE;
  hspi1.Init.CRCPolynomial = 7;
  hspi1.Init.CRCLength = SPI_CRC_LENGTH_DATASIZE;
  hspi1.Init.NSSPMode = SPI_NSS_PULSE_DISABLE;
  if (HAL_SPI_Init(&hspi1) != HAL_OK)
  {
    Error_Handler();
  }
}

static void MX_GPIO_Init(void)
{
  GPIO_InitTypeDef GPIO_InitStruct = {0};

  /* GPIO Ports Clock Enable */
  __HAL_RCC_GPIOF_CLK_ENABLE();
  __HAL_RCC_GPIOH_CLK_ENABLE();
  __HAL_RCC_GPIOC_CLK_ENABLE();
  __HAL_RCC_GPIOA_CLK_ENABLE();
  __HAL_RCC_GPIOG_CLK_ENABLE();
  __HAL_RCC_GPIOE_CLK_ENABLE();
  __HAL_RCC_GPIOB_CLK_ENABLE();
  __HAL_RCC_GPIOD_CLK_ENABLE();

  HAL_GPIO_WritePin(PWM_GPIO_Port, PWM_Pin, GPIO_PIN_RESET);

  /*Configure GPIO pin Output Level */
  HAL_GPIO_WritePin(GPIOF, WDI_Pin | FEC_nRST_Pin, GPIO_PIN_RESET);

  /*Configure GPIO pin Output Level */
  HAL_GPIO_WritePin(GPIOB, conn_5R_Pin | SPI_nCS_Pin | EN_COILPWR_Pin, GPIO_PIN_RESET);

  /*Configure GPIO pin Output Level */
  HAL_GPIO_WritePin(GPIOC, GAIN_2_Pin | GAIN_1_Pin | GAIN_0_Pin, GPIO_PIN_RESET);

  /*Configure GPIO pin Output Level */
  HAL_GPIO_WritePin(GPIOD, TESTLED_R_Pin | TESTLED_G_Pin | RSLED_Pin | WRKLED_R_Pin | WRKLED_G_Pin, GPIO_PIN_RESET);
  HAL_GPIO_WritePin(SPI_nCS_GPIO_Port, SPI_nCS_Pin, GPIO_PIN_SET);

  /*Configure GPIO pins : WDI_Pin FEC_nRST_Pin */
  GPIO_InitStruct.Pin = WDI_Pin | FEC_nRST_Pin;
  GPIO_InitStruct.Mode = GPIO_MODE_OUTPUT_PP;
  GPIO_InitStruct.Pull = GPIO_NOPULL;
  GPIO_InitStruct.Speed = GPIO_SPEED_FREQ_LOW;
  HAL_GPIO_Init(GPIOF, &GPIO_InitStruct);

  /*Configure GPIO pins : conn_5R_Pin SPI_nCS_Pin EN_COILPWR_Pin */
  GPIO_InitStruct.Pin = conn_5R_Pin | SPI_nCS_Pin | EN_COILPWR_Pin;
  GPIO_InitStruct.Mode = GPIO_MODE_OUTPUT_PP;
  GPIO_InitStruct.Pull = GPIO_NOPULL;
  GPIO_InitStruct.Speed = GPIO_SPEED_FREQ_LOW;
  HAL_GPIO_Init(GPIOB, &GPIO_InitStruct);

  /*Configure GPIO pins : conn_10R_Pin conn_2400R_Pin */
  GPIO_InitStruct.Pin = conn_10R_Pin | conn_2400R_Pin;
  GPIO_InitStruct.Mode = GPIO_MODE_OUTPUT_PP;
  GPIO_InitStruct.Pull = GPIO_NOPULL;
  GPIO_InitStruct.Speed = GPIO_SPEED_FREQ_LOW;
  HAL_GPIO_Init(GPIOG, &GPIO_InitStruct);

  /*Configure GPIO pins : FLOAT_TEST_Pin RS_TEST_Pin */
  GPIO_InitStruct.Pin = FLOAT_TEST_Pin | RS_TEST_Pin;
  GPIO_InitStruct.Mode = GPIO_MODE_INPUT;
  GPIO_InitStruct.Pull = GPIO_NOPULL;
  HAL_GPIO_Init(GPIOG, &GPIO_InitStruct);

  /*Configure GPIO pins : GAIN_2_Pin GAIN_1_Pin GAIN_0_Pin */
  GPIO_InitStruct.Pin = GAIN_2_Pin | GAIN_1_Pin | GAIN_0_Pin;
  GPIO_InitStruct.Mode = GPIO_MODE_OUTPUT_PP;
  GPIO_InitStruct.Pull = GPIO_NOPULL;
  GPIO_InitStruct.Speed = GPIO_SPEED_FREQ_LOW;
  HAL_GPIO_Init(GPIOC, &GPIO_InitStruct);

  /*Configure GPIO pins : TESTLED_R_Pin TESTLED_G_Pin RSLED_Pin WRKLED_R_Pin
                           WRKLED_G_Pin */
  GPIO_InitStruct.Pin = TESTLED_R_Pin | TESTLED_G_Pin | RSLED_Pin | WRKLED_R_Pin | WRKLED_G_Pin;
  GPIO_InitStruct.Mode = GPIO_MODE_OUTPUT_PP;
  GPIO_InitStruct.Pull = GPIO_NOPULL;
  GPIO_InitStruct.Speed = GPIO_SPEED_FREQ_LOW;
  HAL_GPIO_Init(GPIOD, &GPIO_InitStruct);

  /*Configure GPIO pin : PB3 */
  GPIO_InitStruct.Pin = GPIO_PIN_3;
  GPIO_InitStruct.Mode = GPIO_MODE_AF_PP;
  GPIO_InitStruct.Pull = GPIO_NOPULL;
  GPIO_InitStruct.Speed = GPIO_SPEED_FREQ_VERY_HIGH;
  GPIO_InitStruct.Alternate = GPIO_AF5_SPI1;
  HAL_GPIO_Init(GPIOB, &GPIO_InitStruct);

  GPIO_InitStruct.Pin = PWM_Pin;
  GPIO_InitStruct.Mode = GPIO_MODE_OUTPUT_PP;
  GPIO_InitStruct.Pull = GPIO_NOPULL;
  GPIO_InitStruct.Speed = GPIO_SPEED_FREQ_LOW;
  HAL_GPIO_Init(PWM_GPIO_Port, &GPIO_InitStruct);
}

void StartDefaultTask(void const *argument)
{
  uint32_t time;
  uint32_t phy_reg;

  /* init code for LWIP */
  MX_LWIP_Init();

  osThreadDef(http_serverTask, http_server, osPriorityNormal, 0, 3072);
  HTTPServerHandle = osThreadCreate(osThread(http_serverTask), NULL);

  for (;;)
  {
    osDelay(10);
    HAL_GPIO_TogglePin(WDI_GPIO_Port, WDI_Pin);
  }
}

void Error_Handler(void)
{
}

/************************ (C) COPYRIGHT STMicroelectronics *****END OF FILE****/
